VERSION 5.7 ;
BUSBITCHARS "[]" ;
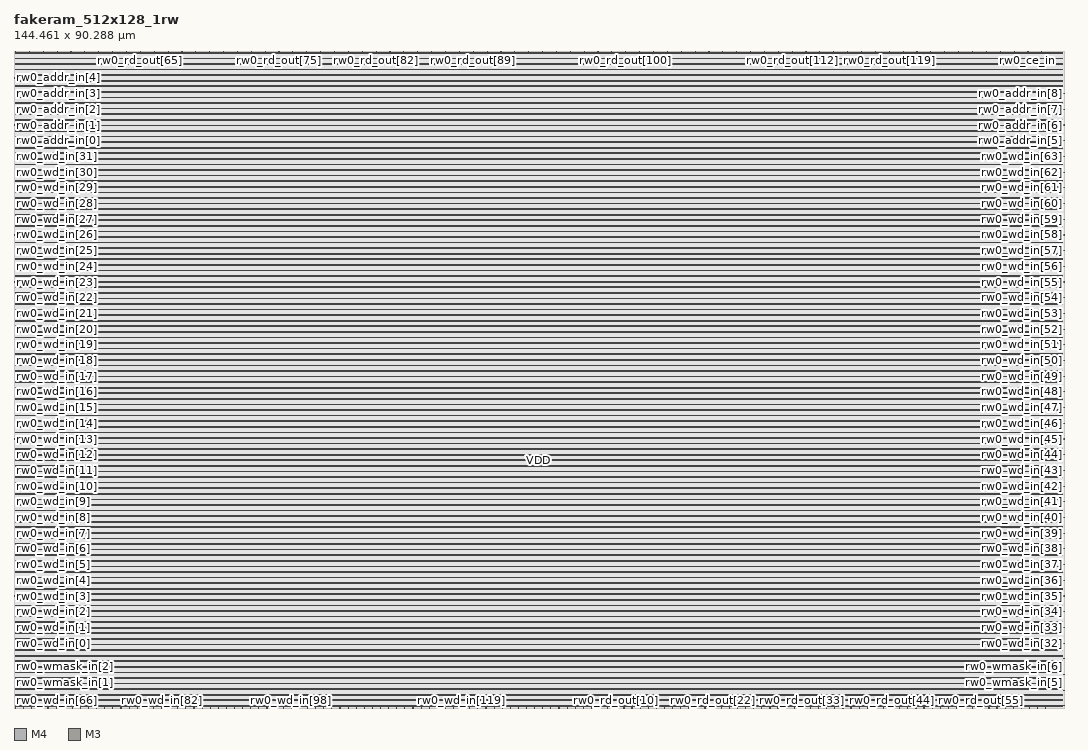
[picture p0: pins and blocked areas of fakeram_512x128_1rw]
MACRO fakeram_512x128_1rw
  FOREIGN fakeram_512x128_1rw 0 0 ;
  SYMMETRY X Y R90 ;
  SIZE 144.461 BY 90.288 ;
  CLASS BLOCK ;
  PIN rw0_wmask_in[0]
    DIRECTION INPUT ;
    USE SIGNAL ;
    SHAPE ABUTMENT ;
    PORT
      LAYER M4 ;
      RECT 0.000 0.276 0.072 0.300 ;
    END
  END rw0_wmask_in[0]
  PIN rw0_wmask_in[1]
    DIRECTION INPUT ;
    USE SIGNAL ;
    SHAPE ABUTMENT ;
    PORT
      LAYER M4 ;
      RECT 0.000 2.436 0.072 2.460 ;
    END
  END rw0_wmask_in[1]
  PIN rw0_wmask_in[2]
    DIRECTION INPUT ;
    USE SIGNAL ;
    SHAPE ABUTMENT ;
    PORT
      LAYER M4 ;
      RECT 0.000 4.596 0.072 4.620 ;
    END
  END rw0_wmask_in[2]
  PIN rw0_wmask_in[3]
    DIRECTION INPUT ;
    USE SIGNAL ;
    SHAPE ABUTMENT ;
    PORT
      LAYER M4 ;
      RECT 0.000 6.756 0.072 6.780 ;
    END
  END rw0_wmask_in[3]
  PIN rw0_wmask_in[4]
    DIRECTION INPUT ;
    USE SIGNAL ;
    SHAPE ABUTMENT ;
    PORT
      LAYER M4 ;
      RECT 144.389 0.276 144.461 0.300 ;
    END
  END rw0_wmask_in[4]
  PIN rw0_wmask_in[5]
    DIRECTION INPUT ;
    USE SIGNAL ;
    SHAPE ABUTMENT ;
    PORT
      LAYER M4 ;
      RECT 144.389 2.436 144.461 2.460 ;
    END
  END rw0_wmask_in[5]
  PIN rw0_wmask_in[6]
    DIRECTION INPUT ;
    USE SIGNAL ;
    SHAPE ABUTMENT ;
    PORT
      LAYER M4 ;
      RECT 144.389 4.596 144.461 4.620 ;
    END
  END rw0_wmask_in[6]
  PIN rw0_wmask_in[7]
    DIRECTION INPUT ;
    USE SIGNAL ;
    SHAPE ABUTMENT ;
    PORT
      LAYER M4 ;
      RECT 144.389 6.756 144.461 6.780 ;
    END
  END rw0_wmask_in[7]
  PIN rw0_wmask_in[8]
    DIRECTION INPUT ;
    USE SIGNAL ;
    SHAPE ABUTMENT ;
    PORT
      LAYER M3 ;
      RECT 0.207 90.234 0.225 90.288 ;
    END
  END rw0_wmask_in[8]
  PIN rw0_wmask_in[9]
    DIRECTION INPUT ;
    USE SIGNAL ;
    SHAPE ABUTMENT ;
    PORT
      LAYER M3 ;
      RECT 2.115 90.234 2.133 90.288 ;
    END
  END rw0_wmask_in[9]
  PIN rw0_wmask_in[10]
    DIRECTION INPUT ;
    USE SIGNAL ;
    SHAPE ABUTMENT ;
    PORT
      LAYER M3 ;
      RECT 4.023 90.234 4.041 90.288 ;
    END
  END rw0_wmask_in[10]
  PIN rw0_wmask_in[11]
    DIRECTION INPUT ;
    USE SIGNAL ;
    SHAPE ABUTMENT ;
    PORT
      LAYER M3 ;
      RECT 5.931 90.234 5.949 90.288 ;
    END
  END rw0_wmask_in[11]
  PIN rw0_wmask_in[12]
    DIRECTION INPUT ;
    USE SIGNAL ;
    SHAPE ABUTMENT ;
    PORT
      LAYER M3 ;
      RECT 7.839 90.234 7.857 90.288 ;
    END
  END rw0_wmask_in[12]
  PIN rw0_wmask_in[13]
    DIRECTION INPUT ;
    USE SIGNAL ;
    SHAPE ABUTMENT ;
    PORT
      LAYER M3 ;
      RECT 9.747 90.234 9.765 90.288 ;
    END
  END rw0_wmask_in[13]
  PIN rw0_wmask_in[14]
    DIRECTION INPUT ;
    USE SIGNAL ;
    SHAPE ABUTMENT ;
    PORT
      LAYER M3 ;
      RECT 11.655 90.234 11.673 90.288 ;
    END
  END rw0_wmask_in[14]
  PIN rw0_wmask_in[15]
    DIRECTION INPUT ;
    USE SIGNAL ;
    SHAPE ABUTMENT ;
    PORT
      LAYER M3 ;
      RECT 13.563 90.234 13.581 90.288 ;
    END
  END rw0_wmask_in[15]
  PIN rw0_wd_in[0]
    DIRECTION INPUT ;
    USE SIGNAL ;
    SHAPE ABUTMENT ;
    PORT
      LAYER M4 ;
      RECT 0.000 8.916 0.072 8.940 ;
    END
  END rw0_wd_in[0]
  PIN rw0_wd_in[1]
    DIRECTION INPUT ;
    USE SIGNAL ;
    SHAPE ABUTMENT ;
    PORT
      LAYER M4 ;
      RECT 0.000 11.076 0.072 11.100 ;
    END
  END rw0_wd_in[1]
  PIN rw0_wd_in[2]
    DIRECTION INPUT ;
    USE SIGNAL ;
    SHAPE ABUTMENT ;
    PORT
      LAYER M4 ;
      RECT 0.000 13.236 0.072 13.260 ;
    END
  END rw0_wd_in[2]
  PIN rw0_wd_in[3]
    DIRECTION INPUT ;
    USE SIGNAL ;
    SHAPE ABUTMENT ;
    PORT
      LAYER M4 ;
      RECT 0.000 15.396 0.072 15.420 ;
    END
  END rw0_wd_in[3]
  PIN rw0_wd_in[4]
    DIRECTION INPUT ;
    USE SIGNAL ;
    SHAPE ABUTMENT ;
    PORT
      LAYER M4 ;
      RECT 0.000 17.556 0.072 17.580 ;
    END
  END rw0_wd_in[4]
  PIN rw0_wd_in[5]
    DIRECTION INPUT ;
    USE SIGNAL ;
    SHAPE ABUTMENT ;
    PORT
      LAYER M4 ;
      RECT 0.000 19.716 0.072 19.740 ;
    END
  END rw0_wd_in[5]
  PIN rw0_wd_in[6]
    DIRECTION INPUT ;
    USE SIGNAL ;
    SHAPE ABUTMENT ;
    PORT
      LAYER M4 ;
      RECT 0.000 21.876 0.072 21.900 ;
    END
  END rw0_wd_in[6]
  PIN rw0_wd_in[7]
    DIRECTION INPUT ;
    USE SIGNAL ;
    SHAPE ABUTMENT ;
    PORT
      LAYER M4 ;
      RECT 0.000 24.036 0.072 24.060 ;
    END
  END rw0_wd_in[7]
  PIN rw0_wd_in[8]
    DIRECTION INPUT ;
    USE SIGNAL ;
    SHAPE ABUTMENT ;
    PORT
      LAYER M4 ;
      RECT 0.000 26.196 0.072 26.220 ;
    END
  END rw0_wd_in[8]
  PIN rw0_wd_in[9]
    DIRECTION INPUT ;
    USE SIGNAL ;
    SHAPE ABUTMENT ;
    PORT
      LAYER M4 ;
      RECT 0.000 28.356 0.072 28.380 ;
    END
  END rw0_wd_in[9]
  PIN rw0_wd_in[10]
    DIRECTION INPUT ;
    USE SIGNAL ;
    SHAPE ABUTMENT ;
    PORT
      LAYER M4 ;
      RECT 0.000 30.516 0.072 30.540 ;
    END
  END rw0_wd_in[10]
  PIN rw0_wd_in[11]
    DIRECTION INPUT ;
    USE SIGNAL ;
    SHAPE ABUTMENT ;
    PORT
      LAYER M4 ;
      RECT 0.000 32.676 0.072 32.700 ;
    END
  END rw0_wd_in[11]
  PIN rw0_wd_in[12]
    DIRECTION INPUT ;
    USE SIGNAL ;
    SHAPE ABUTMENT ;
    PORT
      LAYER M4 ;
      RECT 0.000 34.836 0.072 34.860 ;
    END
  END rw0_wd_in[12]
  PIN rw0_wd_in[13]
    DIRECTION INPUT ;
    USE SIGNAL ;
    SHAPE ABUTMENT ;
    PORT
      LAYER M4 ;
      RECT 0.000 36.996 0.072 37.020 ;
    END
  END rw0_wd_in[13]
  PIN rw0_wd_in[14]
    DIRECTION INPUT ;
    USE SIGNAL ;
    SHAPE ABUTMENT ;
    PORT
      LAYER M4 ;
      RECT 0.000 39.156 0.072 39.180 ;
    END
  END rw0_wd_in[14]
  PIN rw0_wd_in[15]
    DIRECTION INPUT ;
    USE SIGNAL ;
    SHAPE ABUTMENT ;
    PORT
      LAYER M4 ;
      RECT 0.000 41.316 0.072 41.340 ;
    END
  END rw0_wd_in[15]
  PIN rw0_wd_in[16]
    DIRECTION INPUT ;
    USE SIGNAL ;
    SHAPE ABUTMENT ;
    PORT
      LAYER M4 ;
      RECT 0.000 43.476 0.072 43.500 ;
    END
  END rw0_wd_in[16]
  PIN rw0_wd_in[17]
    DIRECTION INPUT ;
    USE SIGNAL ;
    SHAPE ABUTMENT ;
    PORT
      LAYER M4 ;
      RECT 0.000 45.636 0.072 45.660 ;
    END
  END rw0_wd_in[17]
  PIN rw0_wd_in[18]
    DIRECTION INPUT ;
    USE SIGNAL ;
    SHAPE ABUTMENT ;
    PORT
      LAYER M4 ;
      RECT 0.000 47.796 0.072 47.820 ;
    END
  END rw0_wd_in[18]
  PIN rw0_wd_in[19]
    DIRECTION INPUT ;
    USE SIGNAL ;
    SHAPE ABUTMENT ;
    PORT
      LAYER M4 ;
      RECT 0.000 49.956 0.072 49.980 ;
    END
  END rw0_wd_in[19]
  PIN rw0_wd_in[20]
    DIRECTION INPUT ;
    USE SIGNAL ;
    SHAPE ABUTMENT ;
    PORT
      LAYER M4 ;
      RECT 0.000 52.116 0.072 52.140 ;
    END
  END rw0_wd_in[20]
  PIN rw0_wd_in[21]
    DIRECTION INPUT ;
    USE SIGNAL ;
    SHAPE ABUTMENT ;
    PORT
      LAYER M4 ;
      RECT 0.000 54.276 0.072 54.300 ;
    END
  END rw0_wd_in[21]
  PIN rw0_wd_in[22]
    DIRECTION INPUT ;
    USE SIGNAL ;
    SHAPE ABUTMENT ;
    PORT
      LAYER M4 ;
      RECT 0.000 56.436 0.072 56.460 ;
    END
  END rw0_wd_in[22]
  PIN rw0_wd_in[23]
    DIRECTION INPUT ;
    USE SIGNAL ;
    SHAPE ABUTMENT ;
    PORT
      LAYER M4 ;
      RECT 0.000 58.596 0.072 58.620 ;
    END
  END rw0_wd_in[23]
  PIN rw0_wd_in[24]
    DIRECTION INPUT ;
    USE SIGNAL ;
    SHAPE ABUTMENT ;
    PORT
      LAYER M4 ;
      RECT 0.000 60.756 0.072 60.780 ;
    END
  END rw0_wd_in[24]
  PIN rw0_wd_in[25]
    DIRECTION INPUT ;
    USE SIGNAL ;
    SHAPE ABUTMENT ;
    PORT
      LAYER M4 ;
      RECT 0.000 62.916 0.072 62.940 ;
    END
  END rw0_wd_in[25]
  PIN rw0_wd_in[26]
    DIRECTION INPUT ;
    USE SIGNAL ;
    SHAPE ABUTMENT ;
    PORT
      LAYER M4 ;
      RECT 0.000 65.076 0.072 65.100 ;
    END
  END rw0_wd_in[26]
  PIN rw0_wd_in[27]
    DIRECTION INPUT ;
    USE SIGNAL ;
    SHAPE ABUTMENT ;
    PORT
      LAYER M4 ;
      RECT 0.000 67.236 0.072 67.260 ;
    END
  END rw0_wd_in[27]
  PIN rw0_wd_in[28]
    DIRECTION INPUT ;
    USE SIGNAL ;
    SHAPE ABUTMENT ;
    PORT
      LAYER M4 ;
      RECT 0.000 69.396 0.072 69.420 ;
    END
  END rw0_wd_in[28]
  PIN rw0_wd_in[29]
    DIRECTION INPUT ;
    USE SIGNAL ;
    SHAPE ABUTMENT ;
    PORT
      LAYER M4 ;
      RECT 0.000 71.556 0.072 71.580 ;
    END
  END rw0_wd_in[29]
  PIN rw0_wd_in[30]
    DIRECTION INPUT ;
    USE SIGNAL ;
    SHAPE ABUTMENT ;
    PORT
      LAYER M4 ;
      RECT 0.000 73.716 0.072 73.740 ;
    END
  END rw0_wd_in[30]
  PIN rw0_wd_in[31]
    DIRECTION INPUT ;
    USE SIGNAL ;
    SHAPE ABUTMENT ;
    PORT
      LAYER M4 ;
      RECT 0.000 75.876 0.072 75.900 ;
    END
  END rw0_wd_in[31]
  PIN rw0_wd_in[32]
    DIRECTION INPUT ;
    USE SIGNAL ;
    SHAPE ABUTMENT ;
    PORT
      LAYER M4 ;
      RECT 144.389 8.916 144.461 8.940 ;
    END
  END rw0_wd_in[32]
  PIN rw0_wd_in[33]
    DIRECTION INPUT ;
    USE SIGNAL ;
    SHAPE ABUTMENT ;
    PORT
      LAYER M4 ;
      RECT 144.389 11.076 144.461 11.100 ;
    END
  END rw0_wd_in[33]
  PIN rw0_wd_in[34]
    DIRECTION INPUT ;
    USE SIGNAL ;
    SHAPE ABUTMENT ;
    PORT
      LAYER M4 ;
      RECT 144.389 13.236 144.461 13.260 ;
    END
  END rw0_wd_in[34]
  PIN rw0_wd_in[35]
    DIRECTION INPUT ;
    USE SIGNAL ;
    SHAPE ABUTMENT ;
    PORT
      LAYER M4 ;
      RECT 144.389 15.396 144.461 15.420 ;
    END
  END rw0_wd_in[35]
  PIN rw0_wd_in[36]
    DIRECTION INPUT ;
    USE SIGNAL ;
    SHAPE ABUTMENT ;
    PORT
      LAYER M4 ;
      RECT 144.389 17.556 144.461 17.580 ;
    END
  END rw0_wd_in[36]
  PIN rw0_wd_in[37]
    DIRECTION INPUT ;
    USE SIGNAL ;
    SHAPE ABUTMENT ;
    PORT
      LAYER M4 ;
      RECT 144.389 19.716 144.461 19.740 ;
    END
  END rw0_wd_in[37]
  PIN rw0_wd_in[38]
    DIRECTION INPUT ;
    USE SIGNAL ;
    SHAPE ABUTMENT ;
    PORT
      LAYER M4 ;
      RECT 144.389 21.876 144.461 21.900 ;
    END
  END rw0_wd_in[38]
  PIN rw0_wd_in[39]
    DIRECTION INPUT ;
    USE SIGNAL ;
    SHAPE ABUTMENT ;
    PORT
      LAYER M4 ;
      RECT 144.389 24.036 144.461 24.060 ;
    END
  END rw0_wd_in[39]
  PIN rw0_wd_in[40]
    DIRECTION INPUT ;
    USE SIGNAL ;
    SHAPE ABUTMENT ;
    PORT
      LAYER M4 ;
      RECT 144.389 26.196 144.461 26.220 ;
    END
  END rw0_wd_in[40]
  PIN rw0_wd_in[41]
    DIRECTION INPUT ;
    USE SIGNAL ;
    SHAPE ABUTMENT ;
    PORT
      LAYER M4 ;
      RECT 144.389 28.356 144.461 28.380 ;
    END
  END rw0_wd_in[41]
  PIN rw0_wd_in[42]
    DIRECTION INPUT ;
    USE SIGNAL ;
    SHAPE ABUTMENT ;
    PORT
      LAYER M4 ;
      RECT 144.389 30.516 144.461 30.540 ;
    END
  END rw0_wd_in[42]
  PIN rw0_wd_in[43]
    DIRECTION INPUT ;
    USE SIGNAL ;
    SHAPE ABUTMENT ;
    PORT
      LAYER M4 ;
      RECT 144.389 32.676 144.461 32.700 ;
    END
  END rw0_wd_in[43]
  PIN rw0_wd_in[44]
    DIRECTION INPUT ;
    USE SIGNAL ;
    SHAPE ABUTMENT ;
    PORT
      LAYER M4 ;
      RECT 144.389 34.836 144.461 34.860 ;
    END
  END rw0_wd_in[44]
  PIN rw0_wd_in[45]
    DIRECTION INPUT ;
    USE SIGNAL ;
    SHAPE ABUTMENT ;
    PORT
      LAYER M4 ;
      RECT 144.389 36.996 144.461 37.020 ;
    END
  END rw0_wd_in[45]
  PIN rw0_wd_in[46]
    DIRECTION INPUT ;
    USE SIGNAL ;
    SHAPE ABUTMENT ;
    PORT
      LAYER M4 ;
      RECT 144.389 39.156 144.461 39.180 ;
    END
  END rw0_wd_in[46]
  PIN rw0_wd_in[47]
    DIRECTION INPUT ;
    USE SIGNAL ;
    SHAPE ABUTMENT ;
    PORT
      LAYER M4 ;
      RECT 144.389 41.316 144.461 41.340 ;
    END
  END rw0_wd_in[47]
  PIN rw0_wd_in[48]
    DIRECTION INPUT ;
    USE SIGNAL ;
    SHAPE ABUTMENT ;
    PORT
      LAYER M4 ;
      RECT 144.389 43.476 144.461 43.500 ;
    END
  END rw0_wd_in[48]
  PIN rw0_wd_in[49]
    DIRECTION INPUT ;
    USE SIGNAL ;
    SHAPE ABUTMENT ;
    PORT
      LAYER M4 ;
      RECT 144.389 45.636 144.461 45.660 ;
    END
  END rw0_wd_in[49]
  PIN rw0_wd_in[50]
    DIRECTION INPUT ;
    USE SIGNAL ;
    SHAPE ABUTMENT ;
    PORT
      LAYER M4 ;
      RECT 144.389 47.796 144.461 47.820 ;
    END
  END rw0_wd_in[50]
  PIN rw0_wd_in[51]
    DIRECTION INPUT ;
    USE SIGNAL ;
    SHAPE ABUTMENT ;
    PORT
      LAYER M4 ;
      RECT 144.389 49.956 144.461 49.980 ;
    END
  END rw0_wd_in[51]
  PIN rw0_wd_in[52]
    DIRECTION INPUT ;
    USE SIGNAL ;
    SHAPE ABUTMENT ;
    PORT
      LAYER M4 ;
      RECT 144.389 52.116 144.461 52.140 ;
    END
  END rw0_wd_in[52]
  PIN rw0_wd_in[53]
    DIRECTION INPUT ;
    USE SIGNAL ;
    SHAPE ABUTMENT ;
    PORT
      LAYER M4 ;
      RECT 144.389 54.276 144.461 54.300 ;
    END
  END rw0_wd_in[53]
  PIN rw0_wd_in[54]
    DIRECTION INPUT ;
    USE SIGNAL ;
    SHAPE ABUTMENT ;
    PORT
      LAYER M4 ;
      RECT 144.389 56.436 144.461 56.460 ;
    END
  END rw0_wd_in[54]
  PIN rw0_wd_in[55]
    DIRECTION INPUT ;
    USE SIGNAL ;
    SHAPE ABUTMENT ;
    PORT
      LAYER M4 ;
      RECT 144.389 58.596 144.461 58.620 ;
    END
  END rw0_wd_in[55]
  PIN rw0_wd_in[56]
    DIRECTION INPUT ;
    USE SIGNAL ;
    SHAPE ABUTMENT ;
    PORT
      LAYER M4 ;
      RECT 144.389 60.756 144.461 60.780 ;
    END
  END rw0_wd_in[56]
  PIN rw0_wd_in[57]
    DIRECTION INPUT ;
    USE SIGNAL ;
    SHAPE ABUTMENT ;
    PORT
      LAYER M4 ;
      RECT 144.389 62.916 144.461 62.940 ;
    END
  END rw0_wd_in[57]
  PIN rw0_wd_in[58]
    DIRECTION INPUT ;
    USE SIGNAL ;
    SHAPE ABUTMENT ;
    PORT
      LAYER M4 ;
      RECT 144.389 65.076 144.461 65.100 ;
    END
  END rw0_wd_in[58]
  PIN rw0_wd_in[59]
    DIRECTION INPUT ;
    USE SIGNAL ;
    SHAPE ABUTMENT ;
    PORT
      LAYER M4 ;
      RECT 144.389 67.236 144.461 67.260 ;
    END
  END rw0_wd_in[59]
  PIN rw0_wd_in[60]
    DIRECTION INPUT ;
    USE SIGNAL ;
    SHAPE ABUTMENT ;
    PORT
      LAYER M4 ;
      RECT 144.389 69.396 144.461 69.420 ;
    END
  END rw0_wd_in[60]
  PIN rw0_wd_in[61]
    DIRECTION INPUT ;
    USE SIGNAL ;
    SHAPE ABUTMENT ;
    PORT
      LAYER M4 ;
      RECT 144.389 71.556 144.461 71.580 ;
    END
  END rw0_wd_in[61]
  PIN rw0_wd_in[62]
    DIRECTION INPUT ;
    USE SIGNAL ;
    SHAPE ABUTMENT ;
    PORT
      LAYER M4 ;
      RECT 144.389 73.716 144.461 73.740 ;
    END
  END rw0_wd_in[62]
  PIN rw0_wd_in[63]
    DIRECTION INPUT ;
    USE SIGNAL ;
    SHAPE ABUTMENT ;
    PORT
      LAYER M4 ;
      RECT 144.389 75.876 144.461 75.900 ;
    END
  END rw0_wd_in[63]
  PIN rw0_wd_in[64]
    DIRECTION INPUT ;
    USE SIGNAL ;
    SHAPE ABUTMENT ;
    PORT
      LAYER M3 ;
      RECT 0.207 0.000 0.225 0.054 ;
    END
  END rw0_wd_in[64]
  PIN rw0_wd_in[65]
    DIRECTION INPUT ;
    USE SIGNAL ;
    SHAPE ABUTMENT ;
    PORT
      LAYER M3 ;
      RECT 1.323 0.000 1.341 0.054 ;
    END
  END rw0_wd_in[65]
  PIN rw0_wd_in[66]
    DIRECTION INPUT ;
    USE SIGNAL ;
    SHAPE ABUTMENT ;
    PORT
      LAYER M3 ;
      RECT 2.439 0.000 2.457 0.054 ;
    END
  END rw0_wd_in[66]
  PIN rw0_wd_in[67]
    DIRECTION INPUT ;
    USE SIGNAL ;
    SHAPE ABUTMENT ;
    PORT
      LAYER M3 ;
      RECT 3.555 0.000 3.573 0.054 ;
    END
  END rw0_wd_in[67]
  PIN rw0_wd_in[68]
    DIRECTION INPUT ;
    USE SIGNAL ;
    SHAPE ABUTMENT ;
    PORT
      LAYER M3 ;
      RECT 4.671 0.000 4.689 0.054 ;
    END
  END rw0_wd_in[68]
  PIN rw0_wd_in[69]
    DIRECTION INPUT ;
    USE SIGNAL ;
    SHAPE ABUTMENT ;
    PORT
      LAYER M3 ;
      RECT 5.787 0.000 5.805 0.054 ;
    END
  END rw0_wd_in[69]
  PIN rw0_wd_in[70]
    DIRECTION INPUT ;
    USE SIGNAL ;
    SHAPE ABUTMENT ;
    PORT
      LAYER M3 ;
      RECT 6.903 0.000 6.921 0.054 ;
    END
  END rw0_wd_in[70]
  PIN rw0_wd_in[71]
    DIRECTION INPUT ;
    USE SIGNAL ;
    SHAPE ABUTMENT ;
    PORT
      LAYER M3 ;
      RECT 8.019 0.000 8.037 0.054 ;
    END
  END rw0_wd_in[71]
  PIN rw0_wd_in[72]
    DIRECTION INPUT ;
    USE SIGNAL ;
    SHAPE ABUTMENT ;
    PORT
      LAYER M3 ;
      RECT 9.135 0.000 9.153 0.054 ;
    END
  END rw0_wd_in[72]
  PIN rw0_wd_in[73]
    DIRECTION INPUT ;
    USE SIGNAL ;
    SHAPE ABUTMENT ;
    PORT
      LAYER M3 ;
      RECT 10.251 0.000 10.269 0.054 ;
    END
  END rw0_wd_in[73]
  PIN rw0_wd_in[74]
    DIRECTION INPUT ;
    USE SIGNAL ;
    SHAPE ABUTMENT ;
    PORT
      LAYER M3 ;
      RECT 11.367 0.000 11.385 0.054 ;
    END
  END rw0_wd_in[74]
  PIN rw0_wd_in[75]
    DIRECTION INPUT ;
    USE SIGNAL ;
    SHAPE ABUTMENT ;
    PORT
      LAYER M3 ;
      RECT 12.483 0.000 12.501 0.054 ;
    END
  END rw0_wd_in[75]
  PIN rw0_wd_in[76]
    DIRECTION INPUT ;
    USE SIGNAL ;
    SHAPE ABUTMENT ;
    PORT
      LAYER M3 ;
      RECT 13.599 0.000 13.617 0.054 ;
    END
  END rw0_wd_in[76]
  PIN rw0_wd_in[77]
    DIRECTION INPUT ;
    USE SIGNAL ;
    SHAPE ABUTMENT ;
    PORT
      LAYER M3 ;
      RECT 14.715 0.000 14.733 0.054 ;
    END
  END rw0_wd_in[77]
  PIN rw0_wd_in[78]
    DIRECTION INPUT ;
    USE SIGNAL ;
    SHAPE ABUTMENT ;
    PORT
      LAYER M3 ;
      RECT 15.831 0.000 15.849 0.054 ;
    END
  END rw0_wd_in[78]
  PIN rw0_wd_in[79]
    DIRECTION INPUT ;
    USE SIGNAL ;
    SHAPE ABUTMENT ;
    PORT
      LAYER M3 ;
      RECT 16.947 0.000 16.965 0.054 ;
    END
  END rw0_wd_in[79]
  PIN rw0_wd_in[80]
    DIRECTION INPUT ;
    USE SIGNAL ;
    SHAPE ABUTMENT ;
    PORT
      LAYER M3 ;
      RECT 18.063 0.000 18.081 0.054 ;
    END
  END rw0_wd_in[80]
  PIN rw0_wd_in[81]
    DIRECTION INPUT ;
    USE SIGNAL ;
    SHAPE ABUTMENT ;
    PORT
      LAYER M3 ;
      RECT 19.179 0.000 19.197 0.054 ;
    END
  END rw0_wd_in[81]
  PIN rw0_wd_in[82]
    DIRECTION INPUT ;
    USE SIGNAL ;
    SHAPE ABUTMENT ;
    PORT
      LAYER M3 ;
      RECT 20.295 0.000 20.313 0.054 ;
    END
  END rw0_wd_in[82]
  PIN rw0_wd_in[83]
    DIRECTION INPUT ;
    USE SIGNAL ;
    SHAPE ABUTMENT ;
    PORT
      LAYER M3 ;
      RECT 21.411 0.000 21.429 0.054 ;
    END
  END rw0_wd_in[83]
  PIN rw0_wd_in[84]
    DIRECTION INPUT ;
    USE SIGNAL ;
    SHAPE ABUTMENT ;
    PORT
      LAYER M3 ;
      RECT 22.527 0.000 22.545 0.054 ;
    END
  END rw0_wd_in[84]
  PIN rw0_wd_in[85]
    DIRECTION INPUT ;
    USE SIGNAL ;
    SHAPE ABUTMENT ;
    PORT
      LAYER M3 ;
      RECT 23.643 0.000 23.661 0.054 ;
    END
  END rw0_wd_in[85]
  PIN rw0_wd_in[86]
    DIRECTION INPUT ;
    USE SIGNAL ;
    SHAPE ABUTMENT ;
    PORT
      LAYER M3 ;
      RECT 24.759 0.000 24.777 0.054 ;
    END
  END rw0_wd_in[86]
  PIN rw0_wd_in[87]
    DIRECTION INPUT ;
    USE SIGNAL ;
    SHAPE ABUTMENT ;
    PORT
      LAYER M3 ;
      RECT 25.875 0.000 25.893 0.054 ;
    END
  END rw0_wd_in[87]
  PIN rw0_wd_in[88]
    DIRECTION INPUT ;
    USE SIGNAL ;
    SHAPE ABUTMENT ;
    PORT
      LAYER M3 ;
      RECT 26.991 0.000 27.009 0.054 ;
    END
  END rw0_wd_in[88]
  PIN rw0_wd_in[89]
    DIRECTION INPUT ;
    USE SIGNAL ;
    SHAPE ABUTMENT ;
    PORT
      LAYER M3 ;
      RECT 28.107 0.000 28.125 0.054 ;
    END
  END rw0_wd_in[89]
  PIN rw0_wd_in[90]
    DIRECTION INPUT ;
    USE SIGNAL ;
    SHAPE ABUTMENT ;
    PORT
      LAYER M3 ;
      RECT 29.223 0.000 29.241 0.054 ;
    END
  END rw0_wd_in[90]
  PIN rw0_wd_in[91]
    DIRECTION INPUT ;
    USE SIGNAL ;
    SHAPE ABUTMENT ;
    PORT
      LAYER M3 ;
      RECT 30.339 0.000 30.357 0.054 ;
    END
  END rw0_wd_in[91]
  PIN rw0_wd_in[92]
    DIRECTION INPUT ;
    USE SIGNAL ;
    SHAPE ABUTMENT ;
    PORT
      LAYER M3 ;
      RECT 31.455 0.000 31.473 0.054 ;
    END
  END rw0_wd_in[92]
  PIN rw0_wd_in[93]
    DIRECTION INPUT ;
    USE SIGNAL ;
    SHAPE ABUTMENT ;
    PORT
      LAYER M3 ;
      RECT 32.571 0.000 32.589 0.054 ;
    END
  END rw0_wd_in[93]
  PIN rw0_wd_in[94]
    DIRECTION INPUT ;
    USE SIGNAL ;
    SHAPE ABUTMENT ;
    PORT
      LAYER M3 ;
      RECT 33.687 0.000 33.705 0.054 ;
    END
  END rw0_wd_in[94]
  PIN rw0_wd_in[95]
    DIRECTION INPUT ;
    USE SIGNAL ;
    SHAPE ABUTMENT ;
    PORT
      LAYER M3 ;
      RECT 34.803 0.000 34.821 0.054 ;
    END
  END rw0_wd_in[95]
  PIN rw0_wd_in[96]
    DIRECTION INPUT ;
    USE SIGNAL ;
    SHAPE ABUTMENT ;
    PORT
      LAYER M3 ;
      RECT 35.919 0.000 35.937 0.054 ;
    END
  END rw0_wd_in[96]
  PIN rw0_wd_in[97]
    DIRECTION INPUT ;
    USE SIGNAL ;
    SHAPE ABUTMENT ;
    PORT
      LAYER M3 ;
      RECT 37.035 0.000 37.053 0.054 ;
    END
  END rw0_wd_in[97]
  PIN rw0_wd_in[98]
    DIRECTION INPUT ;
    USE SIGNAL ;
    SHAPE ABUTMENT ;
    PORT
      LAYER M3 ;
      RECT 38.151 0.000 38.169 0.054 ;
    END
  END rw0_wd_in[98]
  PIN rw0_wd_in[99]
    DIRECTION INPUT ;
    USE SIGNAL ;
    SHAPE ABUTMENT ;
    PORT
      LAYER M3 ;
      RECT 39.267 0.000 39.285 0.054 ;
    END
  END rw0_wd_in[99]
  PIN rw0_wd_in[100]
    DIRECTION INPUT ;
    USE SIGNAL ;
    SHAPE ABUTMENT ;
    PORT
      LAYER M3 ;
      RECT 40.383 0.000 40.401 0.054 ;
    END
  END rw0_wd_in[100]
  PIN rw0_wd_in[101]
    DIRECTION INPUT ;
    USE SIGNAL ;
    SHAPE ABUTMENT ;
    PORT
      LAYER M3 ;
      RECT 41.499 0.000 41.517 0.054 ;
    END
  END rw0_wd_in[101]
  PIN rw0_wd_in[102]
    DIRECTION INPUT ;
    USE SIGNAL ;
    SHAPE ABUTMENT ;
    PORT
      LAYER M3 ;
      RECT 42.615 0.000 42.633 0.054 ;
    END
  END rw0_wd_in[102]
  PIN rw0_wd_in[103]
    DIRECTION INPUT ;
    USE SIGNAL ;
    SHAPE ABUTMENT ;
    PORT
      LAYER M3 ;
      RECT 43.731 0.000 43.749 0.054 ;
    END
  END rw0_wd_in[103]
  PIN rw0_wd_in[104]
    DIRECTION INPUT ;
    USE SIGNAL ;
    SHAPE ABUTMENT ;
    PORT
      LAYER M3 ;
      RECT 44.847 0.000 44.865 0.054 ;
    END
  END rw0_wd_in[104]
  PIN rw0_wd_in[105]
    DIRECTION INPUT ;
    USE SIGNAL ;
    SHAPE ABUTMENT ;
    PORT
      LAYER M3 ;
      RECT 45.963 0.000 45.981 0.054 ;
    END
  END rw0_wd_in[105]
  PIN rw0_wd_in[106]
    DIRECTION INPUT ;
    USE SIGNAL ;
    SHAPE ABUTMENT ;
    PORT
      LAYER M3 ;
      RECT 47.079 0.000 47.097 0.054 ;
    END
  END rw0_wd_in[106]
  PIN rw0_wd_in[107]
    DIRECTION INPUT ;
    USE SIGNAL ;
    SHAPE ABUTMENT ;
    PORT
      LAYER M3 ;
      RECT 48.195 0.000 48.213 0.054 ;
    END
  END rw0_wd_in[107]
  PIN rw0_wd_in[108]
    DIRECTION INPUT ;
    USE SIGNAL ;
    SHAPE ABUTMENT ;
    PORT
      LAYER M3 ;
      RECT 49.311 0.000 49.329 0.054 ;
    END
  END rw0_wd_in[108]
  PIN rw0_wd_in[109]
    DIRECTION INPUT ;
    USE SIGNAL ;
    SHAPE ABUTMENT ;
    PORT
      LAYER M3 ;
      RECT 50.427 0.000 50.445 0.054 ;
    END
  END rw0_wd_in[109]
  PIN rw0_wd_in[110]
    DIRECTION INPUT ;
    USE SIGNAL ;
    SHAPE ABUTMENT ;
    PORT
      LAYER M3 ;
      RECT 51.543 0.000 51.561 0.054 ;
    END
  END rw0_wd_in[110]
  PIN rw0_wd_in[111]
    DIRECTION INPUT ;
    USE SIGNAL ;
    SHAPE ABUTMENT ;
    PORT
      LAYER M3 ;
      RECT 52.659 0.000 52.677 0.054 ;
    END
  END rw0_wd_in[111]
  PIN rw0_wd_in[112]
    DIRECTION INPUT ;
    USE SIGNAL ;
    SHAPE ABUTMENT ;
    PORT
      LAYER M3 ;
      RECT 53.775 0.000 53.793 0.054 ;
    END
  END rw0_wd_in[112]
  PIN rw0_wd_in[113]
    DIRECTION INPUT ;
    USE SIGNAL ;
    SHAPE ABUTMENT ;
    PORT
      LAYER M3 ;
      RECT 54.891 0.000 54.909 0.054 ;
    END
  END rw0_wd_in[113]
  PIN rw0_wd_in[114]
    DIRECTION INPUT ;
    USE SIGNAL ;
    SHAPE ABUTMENT ;
    PORT
      LAYER M3 ;
      RECT 56.007 0.000 56.025 0.054 ;
    END
  END rw0_wd_in[114]
  PIN rw0_wd_in[115]
    DIRECTION INPUT ;
    USE SIGNAL ;
    SHAPE ABUTMENT ;
    PORT
      LAYER M3 ;
      RECT 57.123 0.000 57.141 0.054 ;
    END
  END rw0_wd_in[115]
  PIN rw0_wd_in[116]
    DIRECTION INPUT ;
    USE SIGNAL ;
    SHAPE ABUTMENT ;
    PORT
      LAYER M3 ;
      RECT 58.239 0.000 58.257 0.054 ;
    END
  END rw0_wd_in[116]
  PIN rw0_wd_in[117]
    DIRECTION INPUT ;
    USE SIGNAL ;
    SHAPE ABUTMENT ;
    PORT
      LAYER M3 ;
      RECT 59.355 0.000 59.373 0.054 ;
    END
  END rw0_wd_in[117]
  PIN rw0_wd_in[118]
    DIRECTION INPUT ;
    USE SIGNAL ;
    SHAPE ABUTMENT ;
    PORT
      LAYER M3 ;
      RECT 60.471 0.000 60.489 0.054 ;
    END
  END rw0_wd_in[118]
  PIN rw0_wd_in[119]
    DIRECTION INPUT ;
    USE SIGNAL ;
    SHAPE ABUTMENT ;
    PORT
      LAYER M3 ;
      RECT 61.587 0.000 61.605 0.054 ;
    END
  END rw0_wd_in[119]
  PIN rw0_wd_in[120]
    DIRECTION INPUT ;
    USE SIGNAL ;
    SHAPE ABUTMENT ;
    PORT
      LAYER M3 ;
      RECT 62.703 0.000 62.721 0.054 ;
    END
  END rw0_wd_in[120]
  PIN rw0_wd_in[121]
    DIRECTION INPUT ;
    USE SIGNAL ;
    SHAPE ABUTMENT ;
    PORT
      LAYER M3 ;
      RECT 63.819 0.000 63.837 0.054 ;
    END
  END rw0_wd_in[121]
  PIN rw0_wd_in[122]
    DIRECTION INPUT ;
    USE SIGNAL ;
    SHAPE ABUTMENT ;
    PORT
      LAYER M3 ;
      RECT 64.935 0.000 64.953 0.054 ;
    END
  END rw0_wd_in[122]
  PIN rw0_wd_in[123]
    DIRECTION INPUT ;
    USE SIGNAL ;
    SHAPE ABUTMENT ;
    PORT
      LAYER M3 ;
      RECT 66.051 0.000 66.069 0.054 ;
    END
  END rw0_wd_in[123]
  PIN rw0_wd_in[124]
    DIRECTION INPUT ;
    USE SIGNAL ;
    SHAPE ABUTMENT ;
    PORT
      LAYER M3 ;
      RECT 67.167 0.000 67.185 0.054 ;
    END
  END rw0_wd_in[124]
  PIN rw0_wd_in[125]
    DIRECTION INPUT ;
    USE SIGNAL ;
    SHAPE ABUTMENT ;
    PORT
      LAYER M3 ;
      RECT 68.283 0.000 68.301 0.054 ;
    END
  END rw0_wd_in[125]
  PIN rw0_wd_in[126]
    DIRECTION INPUT ;
    USE SIGNAL ;
    SHAPE ABUTMENT ;
    PORT
      LAYER M3 ;
      RECT 69.399 0.000 69.417 0.054 ;
    END
  END rw0_wd_in[126]
  PIN rw0_wd_in[127]
    DIRECTION INPUT ;
    USE SIGNAL ;
    SHAPE ABUTMENT ;
    PORT
      LAYER M3 ;
      RECT 70.515 0.000 70.533 0.054 ;
    END
  END rw0_wd_in[127]
  PIN rw0_rd_out[0]
    DIRECTION OUTPUT ;
    USE SIGNAL ;
    SHAPE ABUTMENT ;
    PORT
      LAYER M3 ;
      RECT 71.631 0.000 71.649 0.054 ;
    END
  END rw0_rd_out[0]
  PIN rw0_rd_out[1]
    DIRECTION OUTPUT ;
    USE SIGNAL ;
    SHAPE ABUTMENT ;
    PORT
      LAYER M3 ;
      RECT 72.747 0.000 72.765 0.054 ;
    END
  END rw0_rd_out[1]
  PIN rw0_rd_out[2]
    DIRECTION OUTPUT ;
    USE SIGNAL ;
    SHAPE ABUTMENT ;
    PORT
      LAYER M3 ;
      RECT 73.863 0.000 73.881 0.054 ;
    END
  END rw0_rd_out[2]
  PIN rw0_rd_out[3]
    DIRECTION OUTPUT ;
    USE SIGNAL ;
    SHAPE ABUTMENT ;
    PORT
      LAYER M3 ;
      RECT 74.979 0.000 74.997 0.054 ;
    END
  END rw0_rd_out[3]
  PIN rw0_rd_out[4]
    DIRECTION OUTPUT ;
    USE SIGNAL ;
    SHAPE ABUTMENT ;
    PORT
      LAYER M3 ;
      RECT 76.095 0.000 76.113 0.054 ;
    END
  END rw0_rd_out[4]
  PIN rw0_rd_out[5]
    DIRECTION OUTPUT ;
    USE SIGNAL ;
    SHAPE ABUTMENT ;
    PORT
      LAYER M3 ;
      RECT 77.211 0.000 77.229 0.054 ;
    END
  END rw0_rd_out[5]
  PIN rw0_rd_out[6]
    DIRECTION OUTPUT ;
    USE SIGNAL ;
    SHAPE ABUTMENT ;
    PORT
      LAYER M3 ;
      RECT 78.327 0.000 78.345 0.054 ;
    END
  END rw0_rd_out[6]
  PIN rw0_rd_out[7]
    DIRECTION OUTPUT ;
    USE SIGNAL ;
    SHAPE ABUTMENT ;
    PORT
      LAYER M3 ;
      RECT 79.443 0.000 79.461 0.054 ;
    END
  END rw0_rd_out[7]
  PIN rw0_rd_out[8]
    DIRECTION OUTPUT ;
    USE SIGNAL ;
    SHAPE ABUTMENT ;
    PORT
      LAYER M3 ;
      RECT 80.559 0.000 80.577 0.054 ;
    END
  END rw0_rd_out[8]
  PIN rw0_rd_out[9]
    DIRECTION OUTPUT ;
    USE SIGNAL ;
    SHAPE ABUTMENT ;
    PORT
      LAYER M3 ;
      RECT 81.675 0.000 81.693 0.054 ;
    END
  END rw0_rd_out[9]
  PIN rw0_rd_out[10]
    DIRECTION OUTPUT ;
    USE SIGNAL ;
    SHAPE ABUTMENT ;
    PORT
      LAYER M3 ;
      RECT 82.791 0.000 82.809 0.054 ;
    END
  END rw0_rd_out[10]
  PIN rw0_rd_out[11]
    DIRECTION OUTPUT ;
    USE SIGNAL ;
    SHAPE ABUTMENT ;
    PORT
      LAYER M3 ;
      RECT 83.907 0.000 83.925 0.054 ;
    END
  END rw0_rd_out[11]
  PIN rw0_rd_out[12]
    DIRECTION OUTPUT ;
    USE SIGNAL ;
    SHAPE ABUTMENT ;
    PORT
      LAYER M3 ;
      RECT 85.023 0.000 85.041 0.054 ;
    END
  END rw0_rd_out[12]
  PIN rw0_rd_out[13]
    DIRECTION OUTPUT ;
    USE SIGNAL ;
    SHAPE ABUTMENT ;
    PORT
      LAYER M3 ;
      RECT 86.139 0.000 86.157 0.054 ;
    END
  END rw0_rd_out[13]
  PIN rw0_rd_out[14]
    DIRECTION OUTPUT ;
    USE SIGNAL ;
    SHAPE ABUTMENT ;
    PORT
      LAYER M3 ;
      RECT 87.255 0.000 87.273 0.054 ;
    END
  END rw0_rd_out[14]
  PIN rw0_rd_out[15]
    DIRECTION OUTPUT ;
    USE SIGNAL ;
    SHAPE ABUTMENT ;
    PORT
      LAYER M3 ;
      RECT 88.371 0.000 88.389 0.054 ;
    END
  END rw0_rd_out[15]
  PIN rw0_rd_out[16]
    DIRECTION OUTPUT ;
    USE SIGNAL ;
    SHAPE ABUTMENT ;
    PORT
      LAYER M3 ;
      RECT 89.487 0.000 89.505 0.054 ;
    END
  END rw0_rd_out[16]
  PIN rw0_rd_out[17]
    DIRECTION OUTPUT ;
    USE SIGNAL ;
    SHAPE ABUTMENT ;
    PORT
      LAYER M3 ;
      RECT 90.603 0.000 90.621 0.054 ;
    END
  END rw0_rd_out[17]
  PIN rw0_rd_out[18]
    DIRECTION OUTPUT ;
    USE SIGNAL ;
    SHAPE ABUTMENT ;
    PORT
      LAYER M3 ;
      RECT 91.719 0.000 91.737 0.054 ;
    END
  END rw0_rd_out[18]
  PIN rw0_rd_out[19]
    DIRECTION OUTPUT ;
    USE SIGNAL ;
    SHAPE ABUTMENT ;
    PORT
      LAYER M3 ;
      RECT 92.835 0.000 92.853 0.054 ;
    END
  END rw0_rd_out[19]
  PIN rw0_rd_out[20]
    DIRECTION OUTPUT ;
    USE SIGNAL ;
    SHAPE ABUTMENT ;
    PORT
      LAYER M3 ;
      RECT 93.951 0.000 93.969 0.054 ;
    END
  END rw0_rd_out[20]
  PIN rw0_rd_out[21]
    DIRECTION OUTPUT ;
    USE SIGNAL ;
    SHAPE ABUTMENT ;
    PORT
      LAYER M3 ;
      RECT 95.067 0.000 95.085 0.054 ;
    END
  END rw0_rd_out[21]
  PIN rw0_rd_out[22]
    DIRECTION OUTPUT ;
    USE SIGNAL ;
    SHAPE ABUTMENT ;
    PORT
      LAYER M3 ;
      RECT 96.183 0.000 96.201 0.054 ;
    END
  END rw0_rd_out[22]
  PIN rw0_rd_out[23]
    DIRECTION OUTPUT ;
    USE SIGNAL ;
    SHAPE ABUTMENT ;
    PORT
      LAYER M3 ;
      RECT 97.299 0.000 97.317 0.054 ;
    END
  END rw0_rd_out[23]
  PIN rw0_rd_out[24]
    DIRECTION OUTPUT ;
    USE SIGNAL ;
    SHAPE ABUTMENT ;
    PORT
      LAYER M3 ;
      RECT 98.415 0.000 98.433 0.054 ;
    END
  END rw0_rd_out[24]
  PIN rw0_rd_out[25]
    DIRECTION OUTPUT ;
    USE SIGNAL ;
    SHAPE ABUTMENT ;
    PORT
      LAYER M3 ;
      RECT 99.531 0.000 99.549 0.054 ;
    END
  END rw0_rd_out[25]
  PIN rw0_rd_out[26]
    DIRECTION OUTPUT ;
    USE SIGNAL ;
    SHAPE ABUTMENT ;
    PORT
      LAYER M3 ;
      RECT 100.647 0.000 100.665 0.054 ;
    END
  END rw0_rd_out[26]
  PIN rw0_rd_out[27]
    DIRECTION OUTPUT ;
    USE SIGNAL ;
    SHAPE ABUTMENT ;
    PORT
      LAYER M3 ;
      RECT 101.763 0.000 101.781 0.054 ;
    END
  END rw0_rd_out[27]
  PIN rw0_rd_out[28]
    DIRECTION OUTPUT ;
    USE SIGNAL ;
    SHAPE ABUTMENT ;
    PORT
      LAYER M3 ;
      RECT 102.879 0.000 102.897 0.054 ;
    END
  END rw0_rd_out[28]
  PIN rw0_rd_out[29]
    DIRECTION OUTPUT ;
    USE SIGNAL ;
    SHAPE ABUTMENT ;
    PORT
      LAYER M3 ;
      RECT 103.995 0.000 104.013 0.054 ;
    END
  END rw0_rd_out[29]
  PIN rw0_rd_out[30]
    DIRECTION OUTPUT ;
    USE SIGNAL ;
    SHAPE ABUTMENT ;
    PORT
      LAYER M3 ;
      RECT 105.111 0.000 105.129 0.054 ;
    END
  END rw0_rd_out[30]
  PIN rw0_rd_out[31]
    DIRECTION OUTPUT ;
    USE SIGNAL ;
    SHAPE ABUTMENT ;
    PORT
      LAYER M3 ;
      RECT 106.227 0.000 106.245 0.054 ;
    END
  END rw0_rd_out[31]
  PIN rw0_rd_out[32]
    DIRECTION OUTPUT ;
    USE SIGNAL ;
    SHAPE ABUTMENT ;
    PORT
      LAYER M3 ;
      RECT 107.343 0.000 107.361 0.054 ;
    END
  END rw0_rd_out[32]
  PIN rw0_rd_out[33]
    DIRECTION OUTPUT ;
    USE SIGNAL ;
    SHAPE ABUTMENT ;
    PORT
      LAYER M3 ;
      RECT 108.459 0.000 108.477 0.054 ;
    END
  END rw0_rd_out[33]
  PIN rw0_rd_out[34]
    DIRECTION OUTPUT ;
    USE SIGNAL ;
    SHAPE ABUTMENT ;
    PORT
      LAYER M3 ;
      RECT 109.575 0.000 109.593 0.054 ;
    END
  END rw0_rd_out[34]
  PIN rw0_rd_out[35]
    DIRECTION OUTPUT ;
    USE SIGNAL ;
    SHAPE ABUTMENT ;
    PORT
      LAYER M3 ;
      RECT 110.691 0.000 110.709 0.054 ;
    END
  END rw0_rd_out[35]
  PIN rw0_rd_out[36]
    DIRECTION OUTPUT ;
    USE SIGNAL ;
    SHAPE ABUTMENT ;
    PORT
      LAYER M3 ;
      RECT 111.807 0.000 111.825 0.054 ;
    END
  END rw0_rd_out[36]
  PIN rw0_rd_out[37]
    DIRECTION OUTPUT ;
    USE SIGNAL ;
    SHAPE ABUTMENT ;
    PORT
      LAYER M3 ;
      RECT 112.923 0.000 112.941 0.054 ;
    END
  END rw0_rd_out[37]
  PIN rw0_rd_out[38]
    DIRECTION OUTPUT ;
    USE SIGNAL ;
    SHAPE ABUTMENT ;
    PORT
      LAYER M3 ;
      RECT 114.039 0.000 114.057 0.054 ;
    END
  END rw0_rd_out[38]
  PIN rw0_rd_out[39]
    DIRECTION OUTPUT ;
    USE SIGNAL ;
    SHAPE ABUTMENT ;
    PORT
      LAYER M3 ;
      RECT 115.155 0.000 115.173 0.054 ;
    END
  END rw0_rd_out[39]
  PIN rw0_rd_out[40]
    DIRECTION OUTPUT ;
    USE SIGNAL ;
    SHAPE ABUTMENT ;
    PORT
      LAYER M3 ;
      RECT 116.271 0.000 116.289 0.054 ;
    END
  END rw0_rd_out[40]
  PIN rw0_rd_out[41]
    DIRECTION OUTPUT ;
    USE SIGNAL ;
    SHAPE ABUTMENT ;
    PORT
      LAYER M3 ;
      RECT 117.387 0.000 117.405 0.054 ;
    END
  END rw0_rd_out[41]
  PIN rw0_rd_out[42]
    DIRECTION OUTPUT ;
    USE SIGNAL ;
    SHAPE ABUTMENT ;
    PORT
      LAYER M3 ;
      RECT 118.503 0.000 118.521 0.054 ;
    END
  END rw0_rd_out[42]
  PIN rw0_rd_out[43]
    DIRECTION OUTPUT ;
    USE SIGNAL ;
    SHAPE ABUTMENT ;
    PORT
      LAYER M3 ;
      RECT 119.619 0.000 119.637 0.054 ;
    END
  END rw0_rd_out[43]
  PIN rw0_rd_out[44]
    DIRECTION OUTPUT ;
    USE SIGNAL ;
    SHAPE ABUTMENT ;
    PORT
      LAYER M3 ;
      RECT 120.735 0.000 120.753 0.054 ;
    END
  END rw0_rd_out[44]
  PIN rw0_rd_out[45]
    DIRECTION OUTPUT ;
    USE SIGNAL ;
    SHAPE ABUTMENT ;
    PORT
      LAYER M3 ;
      RECT 121.851 0.000 121.869 0.054 ;
    END
  END rw0_rd_out[45]
  PIN rw0_rd_out[46]
    DIRECTION OUTPUT ;
    USE SIGNAL ;
    SHAPE ABUTMENT ;
    PORT
      LAYER M3 ;
      RECT 122.967 0.000 122.985 0.054 ;
    END
  END rw0_rd_out[46]
  PIN rw0_rd_out[47]
    DIRECTION OUTPUT ;
    USE SIGNAL ;
    SHAPE ABUTMENT ;
    PORT
      LAYER M3 ;
      RECT 124.083 0.000 124.101 0.054 ;
    END
  END rw0_rd_out[47]
  PIN rw0_rd_out[48]
    DIRECTION OUTPUT ;
    USE SIGNAL ;
    SHAPE ABUTMENT ;
    PORT
      LAYER M3 ;
      RECT 125.199 0.000 125.217 0.054 ;
    END
  END rw0_rd_out[48]
  PIN rw0_rd_out[49]
    DIRECTION OUTPUT ;
    USE SIGNAL ;
    SHAPE ABUTMENT ;
    PORT
      LAYER M3 ;
      RECT 126.315 0.000 126.333 0.054 ;
    END
  END rw0_rd_out[49]
  PIN rw0_rd_out[50]
    DIRECTION OUTPUT ;
    USE SIGNAL ;
    SHAPE ABUTMENT ;
    PORT
      LAYER M3 ;
      RECT 127.431 0.000 127.449 0.054 ;
    END
  END rw0_rd_out[50]
  PIN rw0_rd_out[51]
    DIRECTION OUTPUT ;
    USE SIGNAL ;
    SHAPE ABUTMENT ;
    PORT
      LAYER M3 ;
      RECT 128.547 0.000 128.565 0.054 ;
    END
  END rw0_rd_out[51]
  PIN rw0_rd_out[52]
    DIRECTION OUTPUT ;
    USE SIGNAL ;
    SHAPE ABUTMENT ;
    PORT
      LAYER M3 ;
      RECT 129.663 0.000 129.681 0.054 ;
    END
  END rw0_rd_out[52]
  PIN rw0_rd_out[53]
    DIRECTION OUTPUT ;
    USE SIGNAL ;
    SHAPE ABUTMENT ;
    PORT
      LAYER M3 ;
      RECT 130.779 0.000 130.797 0.054 ;
    END
  END rw0_rd_out[53]
  PIN rw0_rd_out[54]
    DIRECTION OUTPUT ;
    USE SIGNAL ;
    SHAPE ABUTMENT ;
    PORT
      LAYER M3 ;
      RECT 131.895 0.000 131.913 0.054 ;
    END
  END rw0_rd_out[54]
  PIN rw0_rd_out[55]
    DIRECTION OUTPUT ;
    USE SIGNAL ;
    SHAPE ABUTMENT ;
    PORT
      LAYER M3 ;
      RECT 133.011 0.000 133.029 0.054 ;
    END
  END rw0_rd_out[55]
  PIN rw0_rd_out[56]
    DIRECTION OUTPUT ;
    USE SIGNAL ;
    SHAPE ABUTMENT ;
    PORT
      LAYER M3 ;
      RECT 134.127 0.000 134.145 0.054 ;
    END
  END rw0_rd_out[56]
  PIN rw0_rd_out[57]
    DIRECTION OUTPUT ;
    USE SIGNAL ;
    SHAPE ABUTMENT ;
    PORT
      LAYER M3 ;
      RECT 135.243 0.000 135.261 0.054 ;
    END
  END rw0_rd_out[57]
  PIN rw0_rd_out[58]
    DIRECTION OUTPUT ;
    USE SIGNAL ;
    SHAPE ABUTMENT ;
    PORT
      LAYER M3 ;
      RECT 136.359 0.000 136.377 0.054 ;
    END
  END rw0_rd_out[58]
  PIN rw0_rd_out[59]
    DIRECTION OUTPUT ;
    USE SIGNAL ;
    SHAPE ABUTMENT ;
    PORT
      LAYER M3 ;
      RECT 137.475 0.000 137.493 0.054 ;
    END
  END rw0_rd_out[59]
  PIN rw0_rd_out[60]
    DIRECTION OUTPUT ;
    USE SIGNAL ;
    SHAPE ABUTMENT ;
    PORT
      LAYER M3 ;
      RECT 138.591 0.000 138.609 0.054 ;
    END
  END rw0_rd_out[60]
  PIN rw0_rd_out[61]
    DIRECTION OUTPUT ;
    USE SIGNAL ;
    SHAPE ABUTMENT ;
    PORT
      LAYER M3 ;
      RECT 139.707 0.000 139.725 0.054 ;
    END
  END rw0_rd_out[61]
  PIN rw0_rd_out[62]
    DIRECTION OUTPUT ;
    USE SIGNAL ;
    SHAPE ABUTMENT ;
    PORT
      LAYER M3 ;
      RECT 140.823 0.000 140.841 0.054 ;
    END
  END rw0_rd_out[62]
  PIN rw0_rd_out[63]
    DIRECTION OUTPUT ;
    USE SIGNAL ;
    SHAPE ABUTMENT ;
    PORT
      LAYER M3 ;
      RECT 141.939 0.000 141.957 0.054 ;
    END
  END rw0_rd_out[63]
  PIN rw0_rd_out[64]
    DIRECTION OUTPUT ;
    USE SIGNAL ;
    SHAPE ABUTMENT ;
    PORT
      LAYER M3 ;
      RECT 15.471 90.234 15.489 90.288 ;
    END
  END rw0_rd_out[64]
  PIN rw0_rd_out[65]
    DIRECTION OUTPUT ;
    USE SIGNAL ;
    SHAPE ABUTMENT ;
    PORT
      LAYER M3 ;
      RECT 17.379 90.234 17.397 90.288 ;
    END
  END rw0_rd_out[65]
  PIN rw0_rd_out[66]
    DIRECTION OUTPUT ;
    USE SIGNAL ;
    SHAPE ABUTMENT ;
    PORT
      LAYER M3 ;
      RECT 19.287 90.234 19.305 90.288 ;
    END
  END rw0_rd_out[66]
  PIN rw0_rd_out[67]
    DIRECTION OUTPUT ;
    USE SIGNAL ;
    SHAPE ABUTMENT ;
    PORT
      LAYER M3 ;
      RECT 21.195 90.234 21.213 90.288 ;
    END
  END rw0_rd_out[67]
  PIN rw0_rd_out[68]
    DIRECTION OUTPUT ;
    USE SIGNAL ;
    SHAPE ABUTMENT ;
    PORT
      LAYER M3 ;
      RECT 23.103 90.234 23.121 90.288 ;
    END
  END rw0_rd_out[68]
  PIN rw0_rd_out[69]
    DIRECTION OUTPUT ;
    USE SIGNAL ;
    SHAPE ABUTMENT ;
    PORT
      LAYER M3 ;
      RECT 25.011 90.234 25.029 90.288 ;
    END
  END rw0_rd_out[69]
  PIN rw0_rd_out[70]
    DIRECTION OUTPUT ;
    USE SIGNAL ;
    SHAPE ABUTMENT ;
    PORT
      LAYER M3 ;
      RECT 26.919 90.234 26.937 90.288 ;
    END
  END rw0_rd_out[70]
  PIN rw0_rd_out[71]
    DIRECTION OUTPUT ;
    USE SIGNAL ;
    SHAPE ABUTMENT ;
    PORT
      LAYER M3 ;
      RECT 28.827 90.234 28.845 90.288 ;
    END
  END rw0_rd_out[71]
  PIN rw0_rd_out[72]
    DIRECTION OUTPUT ;
    USE SIGNAL ;
    SHAPE ABUTMENT ;
    PORT
      LAYER M3 ;
      RECT 30.735 90.234 30.753 90.288 ;
    END
  END rw0_rd_out[72]
  PIN rw0_rd_out[73]
    DIRECTION OUTPUT ;
    USE SIGNAL ;
    SHAPE ABUTMENT ;
    PORT
      LAYER M3 ;
      RECT 32.643 90.234 32.661 90.288 ;
    END
  END rw0_rd_out[73]
  PIN rw0_rd_out[74]
    DIRECTION OUTPUT ;
    USE SIGNAL ;
    SHAPE ABUTMENT ;
    PORT
      LAYER M3 ;
      RECT 34.551 90.234 34.569 90.288 ;
    END
  END rw0_rd_out[74]
  PIN rw0_rd_out[75]
    DIRECTION OUTPUT ;
    USE SIGNAL ;
    SHAPE ABUTMENT ;
    PORT
      LAYER M3 ;
      RECT 36.459 90.234 36.477 90.288 ;
    END
  END rw0_rd_out[75]
  PIN rw0_rd_out[76]
    DIRECTION OUTPUT ;
    USE SIGNAL ;
    SHAPE ABUTMENT ;
    PORT
      LAYER M3 ;
      RECT 38.367 90.234 38.385 90.288 ;
    END
  END rw0_rd_out[76]
  PIN rw0_rd_out[77]
    DIRECTION OUTPUT ;
    USE SIGNAL ;
    SHAPE ABUTMENT ;
    PORT
      LAYER M3 ;
      RECT 40.275 90.234 40.293 90.288 ;
    END
  END rw0_rd_out[77]
  PIN rw0_rd_out[78]
    DIRECTION OUTPUT ;
    USE SIGNAL ;
    SHAPE ABUTMENT ;
    PORT
      LAYER M3 ;
      RECT 42.183 90.234 42.201 90.288 ;
    END
  END rw0_rd_out[78]
  PIN rw0_rd_out[79]
    DIRECTION OUTPUT ;
    USE SIGNAL ;
    SHAPE ABUTMENT ;
    PORT
      LAYER M3 ;
      RECT 44.091 90.234 44.109 90.288 ;
    END
  END rw0_rd_out[79]
  PIN rw0_rd_out[80]
    DIRECTION OUTPUT ;
    USE SIGNAL ;
    SHAPE ABUTMENT ;
    PORT
      LAYER M3 ;
      RECT 45.999 90.234 46.017 90.288 ;
    END
  END rw0_rd_out[80]
  PIN rw0_rd_out[81]
    DIRECTION OUTPUT ;
    USE SIGNAL ;
    SHAPE ABUTMENT ;
    PORT
      LAYER M3 ;
      RECT 47.907 90.234 47.925 90.288 ;
    END
  END rw0_rd_out[81]
  PIN rw0_rd_out[82]
    DIRECTION OUTPUT ;
    USE SIGNAL ;
    SHAPE ABUTMENT ;
    PORT
      LAYER M3 ;
      RECT 49.815 90.234 49.833 90.288 ;
    END
  END rw0_rd_out[82]
  PIN rw0_rd_out[83]
    DIRECTION OUTPUT ;
    USE SIGNAL ;
    SHAPE ABUTMENT ;
    PORT
      LAYER M3 ;
      RECT 51.723 90.234 51.741 90.288 ;
    END
  END rw0_rd_out[83]
  PIN rw0_rd_out[84]
    DIRECTION OUTPUT ;
    USE SIGNAL ;
    SHAPE ABUTMENT ;
    PORT
      LAYER M3 ;
      RECT 53.631 90.234 53.649 90.288 ;
    END
  END rw0_rd_out[84]
  PIN rw0_rd_out[85]
    DIRECTION OUTPUT ;
    USE SIGNAL ;
    SHAPE ABUTMENT ;
    PORT
      LAYER M3 ;
      RECT 55.539 90.234 55.557 90.288 ;
    END
  END rw0_rd_out[85]
  PIN rw0_rd_out[86]
    DIRECTION OUTPUT ;
    USE SIGNAL ;
    SHAPE ABUTMENT ;
    PORT
      LAYER M3 ;
      RECT 57.447 90.234 57.465 90.288 ;
    END
  END rw0_rd_out[86]
  PIN rw0_rd_out[87]
    DIRECTION OUTPUT ;
    USE SIGNAL ;
    SHAPE ABUTMENT ;
    PORT
      LAYER M3 ;
      RECT 59.355 90.234 59.373 90.288 ;
    END
  END rw0_rd_out[87]
  PIN rw0_rd_out[88]
    DIRECTION OUTPUT ;
    USE SIGNAL ;
    SHAPE ABUTMENT ;
    PORT
      LAYER M3 ;
      RECT 61.263 90.234 61.281 90.288 ;
    END
  END rw0_rd_out[88]
  PIN rw0_rd_out[89]
    DIRECTION OUTPUT ;
    USE SIGNAL ;
    SHAPE ABUTMENT ;
    PORT
      LAYER M3 ;
      RECT 63.171 90.234 63.189 90.288 ;
    END
  END rw0_rd_out[89]
  PIN rw0_rd_out[90]
    DIRECTION OUTPUT ;
    USE SIGNAL ;
    SHAPE ABUTMENT ;
    PORT
      LAYER M3 ;
      RECT 65.079 90.234 65.097 90.288 ;
    END
  END rw0_rd_out[90]
  PIN rw0_rd_out[91]
    DIRECTION OUTPUT ;
    USE SIGNAL ;
    SHAPE ABUTMENT ;
    PORT
      LAYER M3 ;
      RECT 66.987 90.234 67.005 90.288 ;
    END
  END rw0_rd_out[91]
  PIN rw0_rd_out[92]
    DIRECTION OUTPUT ;
    USE SIGNAL ;
    SHAPE ABUTMENT ;
    PORT
      LAYER M3 ;
      RECT 68.895 90.234 68.913 90.288 ;
    END
  END rw0_rd_out[92]
  PIN rw0_rd_out[93]
    DIRECTION OUTPUT ;
    USE SIGNAL ;
    SHAPE ABUTMENT ;
    PORT
      LAYER M3 ;
      RECT 70.803 90.234 70.821 90.288 ;
    END
  END rw0_rd_out[93]
  PIN rw0_rd_out[94]
    DIRECTION OUTPUT ;
    USE SIGNAL ;
    SHAPE ABUTMENT ;
    PORT
      LAYER M3 ;
      RECT 72.711 90.234 72.729 90.288 ;
    END
  END rw0_rd_out[94]
  PIN rw0_rd_out[95]
    DIRECTION OUTPUT ;
    USE SIGNAL ;
    SHAPE ABUTMENT ;
    PORT
      LAYER M3 ;
      RECT 74.619 90.234 74.637 90.288 ;
    END
  END rw0_rd_out[95]
  PIN rw0_rd_out[96]
    DIRECTION OUTPUT ;
    USE SIGNAL ;
    SHAPE ABUTMENT ;
    PORT
      LAYER M3 ;
      RECT 76.527 90.234 76.545 90.288 ;
    END
  END rw0_rd_out[96]
  PIN rw0_rd_out[97]
    DIRECTION OUTPUT ;
    USE SIGNAL ;
    SHAPE ABUTMENT ;
    PORT
      LAYER M3 ;
      RECT 78.435 90.234 78.453 90.288 ;
    END
  END rw0_rd_out[97]
  PIN rw0_rd_out[98]
    DIRECTION OUTPUT ;
    USE SIGNAL ;
    SHAPE ABUTMENT ;
    PORT
      LAYER M3 ;
      RECT 80.343 90.234 80.361 90.288 ;
    END
  END rw0_rd_out[98]
  PIN rw0_rd_out[99]
    DIRECTION OUTPUT ;
    USE SIGNAL ;
    SHAPE ABUTMENT ;
    PORT
      LAYER M3 ;
      RECT 82.251 90.234 82.269 90.288 ;
    END
  END rw0_rd_out[99]
  PIN rw0_rd_out[100]
    DIRECTION OUTPUT ;
    USE SIGNAL ;
    SHAPE ABUTMENT ;
    PORT
      LAYER M3 ;
      RECT 84.159 90.234 84.177 90.288 ;
    END
  END rw0_rd_out[100]
  PIN rw0_rd_out[101]
    DIRECTION OUTPUT ;
    USE SIGNAL ;
    SHAPE ABUTMENT ;
    PORT
      LAYER M3 ;
      RECT 86.067 90.234 86.085 90.288 ;
    END
  END rw0_rd_out[101]
  PIN rw0_rd_out[102]
    DIRECTION OUTPUT ;
    USE SIGNAL ;
    SHAPE ABUTMENT ;
    PORT
      LAYER M3 ;
      RECT 87.975 90.234 87.993 90.288 ;
    END
  END rw0_rd_out[102]
  PIN rw0_rd_out[103]
    DIRECTION OUTPUT ;
    USE SIGNAL ;
    SHAPE ABUTMENT ;
    PORT
      LAYER M3 ;
      RECT 89.883 90.234 89.901 90.288 ;
    END
  END rw0_rd_out[103]
  PIN rw0_rd_out[104]
    DIRECTION OUTPUT ;
    USE SIGNAL ;
    SHAPE ABUTMENT ;
    PORT
      LAYER M3 ;
      RECT 91.791 90.234 91.809 90.288 ;
    END
  END rw0_rd_out[104]
  PIN rw0_rd_out[105]
    DIRECTION OUTPUT ;
    USE SIGNAL ;
    SHAPE ABUTMENT ;
    PORT
      LAYER M3 ;
      RECT 93.699 90.234 93.717 90.288 ;
    END
  END rw0_rd_out[105]
  PIN rw0_rd_out[106]
    DIRECTION OUTPUT ;
    USE SIGNAL ;
    SHAPE ABUTMENT ;
    PORT
      LAYER M3 ;
      RECT 95.607 90.234 95.625 90.288 ;
    END
  END rw0_rd_out[106]
  PIN rw0_rd_out[107]
    DIRECTION OUTPUT ;
    USE SIGNAL ;
    SHAPE ABUTMENT ;
    PORT
      LAYER M3 ;
      RECT 97.515 90.234 97.533 90.288 ;
    END
  END rw0_rd_out[107]
  PIN rw0_rd_out[108]
    DIRECTION OUTPUT ;
    USE SIGNAL ;
    SHAPE ABUTMENT ;
    PORT
      LAYER M3 ;
      RECT 99.423 90.234 99.441 90.288 ;
    END
  END rw0_rd_out[108]
  PIN rw0_rd_out[109]
    DIRECTION OUTPUT ;
    USE SIGNAL ;
    SHAPE ABUTMENT ;
    PORT
      LAYER M3 ;
      RECT 101.331 90.234 101.349 90.288 ;
    END
  END rw0_rd_out[109]
  PIN rw0_rd_out[110]
    DIRECTION OUTPUT ;
    USE SIGNAL ;
    SHAPE ABUTMENT ;
    PORT
      LAYER M3 ;
      RECT 103.239 90.234 103.257 90.288 ;
    END
  END rw0_rd_out[110]
  PIN rw0_rd_out[111]
    DIRECTION OUTPUT ;
    USE SIGNAL ;
    SHAPE ABUTMENT ;
    PORT
      LAYER M3 ;
      RECT 105.147 90.234 105.165 90.288 ;
    END
  END rw0_rd_out[111]
  PIN rw0_rd_out[112]
    DIRECTION OUTPUT ;
    USE SIGNAL ;
    SHAPE ABUTMENT ;
    PORT
      LAYER M3 ;
      RECT 107.055 90.234 107.073 90.288 ;
    END
  END rw0_rd_out[112]
  PIN rw0_rd_out[113]
    DIRECTION OUTPUT ;
    USE SIGNAL ;
    SHAPE ABUTMENT ;
    PORT
      LAYER M3 ;
      RECT 108.963 90.234 108.981 90.288 ;
    END
  END rw0_rd_out[113]
  PIN rw0_rd_out[114]
    DIRECTION OUTPUT ;
    USE SIGNAL ;
    SHAPE ABUTMENT ;
    PORT
      LAYER M3 ;
      RECT 110.871 90.234 110.889 90.288 ;
    END
  END rw0_rd_out[114]
  PIN rw0_rd_out[115]
    DIRECTION OUTPUT ;
    USE SIGNAL ;
    SHAPE ABUTMENT ;
    PORT
      LAYER M3 ;
      RECT 112.779 90.234 112.797 90.288 ;
    END
  END rw0_rd_out[115]
  PIN rw0_rd_out[116]
    DIRECTION OUTPUT ;
    USE SIGNAL ;
    SHAPE ABUTMENT ;
    PORT
      LAYER M3 ;
      RECT 114.687 90.234 114.705 90.288 ;
    END
  END rw0_rd_out[116]
  PIN rw0_rd_out[117]
    DIRECTION OUTPUT ;
    USE SIGNAL ;
    SHAPE ABUTMENT ;
    PORT
      LAYER M3 ;
      RECT 116.595 90.234 116.613 90.288 ;
    END
  END rw0_rd_out[117]
  PIN rw0_rd_out[118]
    DIRECTION OUTPUT ;
    USE SIGNAL ;
    SHAPE ABUTMENT ;
    PORT
      LAYER M3 ;
      RECT 118.503 90.234 118.521 90.288 ;
    END
  END rw0_rd_out[118]
  PIN rw0_rd_out[119]
    DIRECTION OUTPUT ;
    USE SIGNAL ;
    SHAPE ABUTMENT ;
    PORT
      LAYER M3 ;
      RECT 120.411 90.234 120.429 90.288 ;
    END
  END rw0_rd_out[119]
  PIN rw0_rd_out[120]
    DIRECTION OUTPUT ;
    USE SIGNAL ;
    SHAPE ABUTMENT ;
    PORT
      LAYER M3 ;
      RECT 122.319 90.234 122.337 90.288 ;
    END
  END rw0_rd_out[120]
  PIN rw0_rd_out[121]
    DIRECTION OUTPUT ;
    USE SIGNAL ;
    SHAPE ABUTMENT ;
    PORT
      LAYER M3 ;
      RECT 124.227 90.234 124.245 90.288 ;
    END
  END rw0_rd_out[121]
  PIN rw0_rd_out[122]
    DIRECTION OUTPUT ;
    USE SIGNAL ;
    SHAPE ABUTMENT ;
    PORT
      LAYER M3 ;
      RECT 126.135 90.234 126.153 90.288 ;
    END
  END rw0_rd_out[122]
  PIN rw0_rd_out[123]
    DIRECTION OUTPUT ;
    USE SIGNAL ;
    SHAPE ABUTMENT ;
    PORT
      LAYER M3 ;
      RECT 128.043 90.234 128.061 90.288 ;
    END
  END rw0_rd_out[123]
  PIN rw0_rd_out[124]
    DIRECTION OUTPUT ;
    USE SIGNAL ;
    SHAPE ABUTMENT ;
    PORT
      LAYER M3 ;
      RECT 129.951 90.234 129.969 90.288 ;
    END
  END rw0_rd_out[124]
  PIN rw0_rd_out[125]
    DIRECTION OUTPUT ;
    USE SIGNAL ;
    SHAPE ABUTMENT ;
    PORT
      LAYER M3 ;
      RECT 131.859 90.234 131.877 90.288 ;
    END
  END rw0_rd_out[125]
  PIN rw0_rd_out[126]
    DIRECTION OUTPUT ;
    USE SIGNAL ;
    SHAPE ABUTMENT ;
    PORT
      LAYER M3 ;
      RECT 133.767 90.234 133.785 90.288 ;
    END
  END rw0_rd_out[126]
  PIN rw0_rd_out[127]
    DIRECTION OUTPUT ;
    USE SIGNAL ;
    SHAPE ABUTMENT ;
    PORT
      LAYER M3 ;
      RECT 135.675 90.234 135.693 90.288 ;
    END
  END rw0_rd_out[127]
  PIN rw0_addr_in[0]
    DIRECTION INPUT ;
    USE SIGNAL ;
    SHAPE ABUTMENT ;
    PORT
      LAYER M4 ;
      RECT 0.000 78.036 0.072 78.060 ;
    END
  END rw0_addr_in[0]
  PIN rw0_addr_in[1]
    DIRECTION INPUT ;
    USE SIGNAL ;
    SHAPE ABUTMENT ;
    PORT
      LAYER M4 ;
      RECT 0.000 80.196 0.072 80.220 ;
    END
  END rw0_addr_in[1]
  PIN rw0_addr_in[2]
    DIRECTION INPUT ;
    USE SIGNAL ;
    SHAPE ABUTMENT ;
    PORT
      LAYER M4 ;
      RECT 0.000 82.356 0.072 82.380 ;
    END
  END rw0_addr_in[2]
  PIN rw0_addr_in[3]
    DIRECTION INPUT ;
    USE SIGNAL ;
    SHAPE ABUTMENT ;
    PORT
      LAYER M4 ;
      RECT 0.000 84.516 0.072 84.540 ;
    END
  END rw0_addr_in[3]
  PIN rw0_addr_in[4]
    DIRECTION INPUT ;
    USE SIGNAL ;
    SHAPE ABUTMENT ;
    PORT
      LAYER M4 ;
      RECT 0.000 86.676 0.072 86.700 ;
    END
  END rw0_addr_in[4]
  PIN rw0_addr_in[5]
    DIRECTION INPUT ;
    USE SIGNAL ;
    SHAPE ABUTMENT ;
    PORT
      LAYER M4 ;
      RECT 144.389 78.036 144.461 78.060 ;
    END
  END rw0_addr_in[5]
  PIN rw0_addr_in[6]
    DIRECTION INPUT ;
    USE SIGNAL ;
    SHAPE ABUTMENT ;
    PORT
      LAYER M4 ;
      RECT 144.389 80.196 144.461 80.220 ;
    END
  END rw0_addr_in[6]
  PIN rw0_addr_in[7]
    DIRECTION INPUT ;
    USE SIGNAL ;
    SHAPE ABUTMENT ;
    PORT
      LAYER M4 ;
      RECT 144.389 82.356 144.461 82.380 ;
    END
  END rw0_addr_in[7]
  PIN rw0_addr_in[8]
    DIRECTION INPUT ;
    USE SIGNAL ;
    SHAPE ABUTMENT ;
    PORT
      LAYER M4 ;
      RECT 144.389 84.516 144.461 84.540 ;
    END
  END rw0_addr_in[8]
  PIN rw0_we_in
    DIRECTION INPUT ;
    USE SIGNAL ;
    SHAPE ABUTMENT ;
    PORT
      LAYER M3 ;
      RECT 137.583 90.234 137.601 90.288 ;
    END
  END rw0_we_in
  PIN rw0_ce_in
    DIRECTION INPUT ;
    USE SIGNAL ;
    SHAPE ABUTMENT ;
    PORT
      LAYER M3 ;
      RECT 139.491 90.234 139.509 90.288 ;
    END
  END rw0_ce_in
  PIN rw0_clk
    DIRECTION INPUT ;
    USE SIGNAL ;
    SHAPE ABUTMENT ;
    PORT
      LAYER M3 ;
      RECT 141.399 90.234 141.417 90.288 ;
    END
  END rw0_clk
  PIN VSS
    DIRECTION INOUT ;
    USE GROUND ;
    PORT
      LAYER M4 ;
      RECT 0.216 0.240 144.245 0.336 ;
      RECT 0.216 1.008 144.245 1.104 ;
      RECT 0.216 1.776 144.245 1.872 ;
      RECT 0.216 2.544 144.245 2.640 ;
      RECT 0.216 3.312 144.245 3.408 ;
      RECT 0.216 4.080 144.245 4.176 ;
      RECT 0.216 4.848 144.245 4.944 ;
      RECT 0.216 5.616 144.245 5.712 ;
      RECT 0.216 6.384 144.245 6.480 ;
      RECT 0.216 7.152 144.245 7.248 ;
      RECT 0.216 7.920 144.245 8.016 ;
      RECT 0.216 8.688 144.245 8.784 ;
      RECT 0.216 9.456 144.245 9.552 ;
      RECT 0.216 10.224 144.245 10.320 ;
      RECT 0.216 10.992 144.245 11.088 ;
      RECT 0.216 11.760 144.245 11.856 ;
      RECT 0.216 12.528 144.245 12.624 ;
      RECT 0.216 13.296 144.245 13.392 ;
      RECT 0.216 14.064 144.245 14.160 ;
      RECT 0.216 14.832 144.245 14.928 ;
      RECT 0.216 15.600 144.245 15.696 ;
      RECT 0.216 16.368 144.245 16.464 ;
      RECT 0.216 17.136 144.245 17.232 ;
      RECT 0.216 17.904 144.245 18.000 ;
      RECT 0.216 18.672 144.245 18.768 ;
      RECT 0.216 19.440 144.245 19.536 ;
      RECT 0.216 20.208 144.245 20.304 ;
      RECT 0.216 20.976 144.245 21.072 ;
      RECT 0.216 21.744 144.245 21.840 ;
      RECT 0.216 22.512 144.245 22.608 ;
      RECT 0.216 23.280 144.245 23.376 ;
      RECT 0.216 24.048 144.245 24.144 ;
      RECT 0.216 24.816 144.245 24.912 ;
      RECT 0.216 25.584 144.245 25.680 ;
      RECT 0.216 26.352 144.245 26.448 ;
      RECT 0.216 27.120 144.245 27.216 ;
      RECT 0.216 27.888 144.245 27.984 ;
      RECT 0.216 28.656 144.245 28.752 ;
      RECT 0.216 29.424 144.245 29.520 ;
      RECT 0.216 30.192 144.245 30.288 ;
      RECT 0.216 30.960 144.245 31.056 ;
      RECT 0.216 31.728 144.245 31.824 ;
      RECT 0.216 32.496 144.245 32.592 ;
      RECT 0.216 33.264 144.245 33.360 ;
      RECT 0.216 34.032 144.245 34.128 ;
      RECT 0.216 34.800 144.245 34.896 ;
      RECT 0.216 35.568 144.245 35.664 ;
      RECT 0.216 36.336 144.245 36.432 ;
      RECT 0.216 37.104 144.245 37.200 ;
      RECT 0.216 37.872 144.245 37.968 ;
      RECT 0.216 38.640 144.245 38.736 ;
      RECT 0.216 39.408 144.245 39.504 ;
      RECT 0.216 40.176 144.245 40.272 ;
      RECT 0.216 40.944 144.245 41.040 ;
      RECT 0.216 41.712 144.245 41.808 ;
      RECT 0.216 42.480 144.245 42.576 ;
      RECT 0.216 43.248 144.245 43.344 ;
      RECT 0.216 44.016 144.245 44.112 ;
      RECT 0.216 44.784 144.245 44.880 ;
      RECT 0.216 45.552 144.245 45.648 ;
      RECT 0.216 46.320 144.245 46.416 ;
      RECT 0.216 47.088 144.245 47.184 ;
      RECT 0.216 47.856 144.245 47.952 ;
      RECT 0.216 48.624 144.245 48.720 ;
      RECT 0.216 49.392 144.245 49.488 ;
      RECT 0.216 50.160 144.245 50.256 ;
      RECT 0.216 50.928 144.245 51.024 ;
      RECT 0.216 51.696 144.245 51.792 ;
      RECT 0.216 52.464 144.245 52.560 ;
      RECT 0.216 53.232 144.245 53.328 ;
      RECT 0.216 54.000 144.245 54.096 ;
      RECT 0.216 54.768 144.245 54.864 ;
      RECT 0.216 55.536 144.245 55.632 ;
      RECT 0.216 56.304 144.245 56.400 ;
      RECT 0.216 57.072 144.245 57.168 ;
      RECT 0.216 57.840 144.245 57.936 ;
      RECT 0.216 58.608 144.245 58.704 ;
      RECT 0.216 59.376 144.245 59.472 ;
      RECT 0.216 60.144 144.245 60.240 ;
      RECT 0.216 60.912 144.245 61.008 ;
      RECT 0.216 61.680 144.245 61.776 ;
      RECT 0.216 62.448 144.245 62.544 ;
      RECT 0.216 63.216 144.245 63.312 ;
      RECT 0.216 63.984 144.245 64.080 ;
      RECT 0.216 64.752 144.245 64.848 ;
      RECT 0.216 65.520 144.245 65.616 ;
      RECT 0.216 66.288 144.245 66.384 ;
      RECT 0.216 67.056 144.245 67.152 ;
      RECT 0.216 67.824 144.245 67.920 ;
      RECT 0.216 68.592 144.245 68.688 ;
      RECT 0.216 69.360 144.245 69.456 ;
      RECT 0.216 70.128 144.245 70.224 ;
      RECT 0.216 70.896 144.245 70.992 ;
      RECT 0.216 71.664 144.245 71.760 ;
      RECT 0.216 72.432 144.245 72.528 ;
      RECT 0.216 73.200 144.245 73.296 ;
      RECT 0.216 73.968 144.245 74.064 ;
      RECT 0.216 74.736 144.245 74.832 ;
      RECT 0.216 75.504 144.245 75.600 ;
      RECT 0.216 76.272 144.245 76.368 ;
      RECT 0.216 77.040 144.245 77.136 ;
      RECT 0.216 77.808 144.245 77.904 ;
      RECT 0.216 78.576 144.245 78.672 ;
      RECT 0.216 79.344 144.245 79.440 ;
      RECT 0.216 80.112 144.245 80.208 ;
      RECT 0.216 80.880 144.245 80.976 ;
      RECT 0.216 81.648 144.245 81.744 ;
      RECT 0.216 82.416 144.245 82.512 ;
      RECT 0.216 83.184 144.245 83.280 ;
      RECT 0.216 83.952 144.245 84.048 ;
      RECT 0.216 84.720 144.245 84.816 ;
      RECT 0.216 85.488 144.245 85.584 ;
      RECT 0.216 86.256 144.245 86.352 ;
      RECT 0.216 87.024 144.245 87.120 ;
      RECT 0.216 87.792 144.245 87.888 ;
      RECT 0.216 88.560 144.245 88.656 ;
      RECT 0.216 89.328 144.245 89.424 ;
      RECT 0.216 90.096 144.245 90.192 ;
    END
  END VSS
  PIN VDD
    DIRECTION INOUT ;
    USE POWER ;
    PORT
      LAYER M4 ;
      RECT 0.216 0.240 144.245 0.336 ;
      RECT 0.216 1.008 144.245 1.104 ;
      RECT 0.216 1.776 144.245 1.872 ;
      RECT 0.216 2.544 144.245 2.640 ;
      RECT 0.216 3.312 144.245 3.408 ;
      RECT 0.216 4.080 144.245 4.176 ;
      RECT 0.216 4.848 144.245 4.944 ;
      RECT 0.216 5.616 144.245 5.712 ;
      RECT 0.216 6.384 144.245 6.480 ;
      RECT 0.216 7.152 144.245 7.248 ;
      RECT 0.216 7.920 144.245 8.016 ;
      RECT 0.216 8.688 144.245 8.784 ;
      RECT 0.216 9.456 144.245 9.552 ;
      RECT 0.216 10.224 144.245 10.320 ;
      RECT 0.216 10.992 144.245 11.088 ;
      RECT 0.216 11.760 144.245 11.856 ;
      RECT 0.216 12.528 144.245 12.624 ;
      RECT 0.216 13.296 144.245 13.392 ;
      RECT 0.216 14.064 144.245 14.160 ;
      RECT 0.216 14.832 144.245 14.928 ;
      RECT 0.216 15.600 144.245 15.696 ;
      RECT 0.216 16.368 144.245 16.464 ;
      RECT 0.216 17.136 144.245 17.232 ;
      RECT 0.216 17.904 144.245 18.000 ;
      RECT 0.216 18.672 144.245 18.768 ;
      RECT 0.216 19.440 144.245 19.536 ;
      RECT 0.216 20.208 144.245 20.304 ;
      RECT 0.216 20.976 144.245 21.072 ;
      RECT 0.216 21.744 144.245 21.840 ;
      RECT 0.216 22.512 144.245 22.608 ;
      RECT 0.216 23.280 144.245 23.376 ;
      RECT 0.216 24.048 144.245 24.144 ;
      RECT 0.216 24.816 144.245 24.912 ;
      RECT 0.216 25.584 144.245 25.680 ;
      RECT 0.216 26.352 144.245 26.448 ;
      RECT 0.216 27.120 144.245 27.216 ;
      RECT 0.216 27.888 144.245 27.984 ;
      RECT 0.216 28.656 144.245 28.752 ;
      RECT 0.216 29.424 144.245 29.520 ;
      RECT 0.216 30.192 144.245 30.288 ;
      RECT 0.216 30.960 144.245 31.056 ;
      RECT 0.216 31.728 144.245 31.824 ;
      RECT 0.216 32.496 144.245 32.592 ;
      RECT 0.216 33.264 144.245 33.360 ;
      RECT 0.216 34.032 144.245 34.128 ;
      RECT 0.216 34.800 144.245 34.896 ;
      RECT 0.216 35.568 144.245 35.664 ;
      RECT 0.216 36.336 144.245 36.432 ;
      RECT 0.216 37.104 144.245 37.200 ;
      RECT 0.216 37.872 144.245 37.968 ;
      RECT 0.216 38.640 144.245 38.736 ;
      RECT 0.216 39.408 144.245 39.504 ;
      RECT 0.216 40.176 144.245 40.272 ;
      RECT 0.216 40.944 144.245 41.040 ;
      RECT 0.216 41.712 144.245 41.808 ;
      RECT 0.216 42.480 144.245 42.576 ;
      RECT 0.216 43.248 144.245 43.344 ;
      RECT 0.216 44.016 144.245 44.112 ;
      RECT 0.216 44.784 144.245 44.880 ;
      RECT 0.216 45.552 144.245 45.648 ;
      RECT 0.216 46.320 144.245 46.416 ;
      RECT 0.216 47.088 144.245 47.184 ;
      RECT 0.216 47.856 144.245 47.952 ;
      RECT 0.216 48.624 144.245 48.720 ;
      RECT 0.216 49.392 144.245 49.488 ;
      RECT 0.216 50.160 144.245 50.256 ;
      RECT 0.216 50.928 144.245 51.024 ;
      RECT 0.216 51.696 144.245 51.792 ;
      RECT 0.216 52.464 144.245 52.560 ;
      RECT 0.216 53.232 144.245 53.328 ;
      RECT 0.216 54.000 144.245 54.096 ;
      RECT 0.216 54.768 144.245 54.864 ;
      RECT 0.216 55.536 144.245 55.632 ;
      RECT 0.216 56.304 144.245 56.400 ;
      RECT 0.216 57.072 144.245 57.168 ;
      RECT 0.216 57.840 144.245 57.936 ;
      RECT 0.216 58.608 144.245 58.704 ;
      RECT 0.216 59.376 144.245 59.472 ;
      RECT 0.216 60.144 144.245 60.240 ;
      RECT 0.216 60.912 144.245 61.008 ;
      RECT 0.216 61.680 144.245 61.776 ;
      RECT 0.216 62.448 144.245 62.544 ;
      RECT 0.216 63.216 144.245 63.312 ;
      RECT 0.216 63.984 144.245 64.080 ;
      RECT 0.216 64.752 144.245 64.848 ;
      RECT 0.216 65.520 144.245 65.616 ;
      RECT 0.216 66.288 144.245 66.384 ;
      RECT 0.216 67.056 144.245 67.152 ;
      RECT 0.216 67.824 144.245 67.920 ;
      RECT 0.216 68.592 144.245 68.688 ;
      RECT 0.216 69.360 144.245 69.456 ;
      RECT 0.216 70.128 144.245 70.224 ;
      RECT 0.216 70.896 144.245 70.992 ;
      RECT 0.216 71.664 144.245 71.760 ;
      RECT 0.216 72.432 144.245 72.528 ;
      RECT 0.216 73.200 144.245 73.296 ;
      RECT 0.216 73.968 144.245 74.064 ;
      RECT 0.216 74.736 144.245 74.832 ;
      RECT 0.216 75.504 144.245 75.600 ;
      RECT 0.216 76.272 144.245 76.368 ;
      RECT 0.216 77.040 144.245 77.136 ;
      RECT 0.216 77.808 144.245 77.904 ;
      RECT 0.216 78.576 144.245 78.672 ;
      RECT 0.216 79.344 144.245 79.440 ;
      RECT 0.216 80.112 144.245 80.208 ;
      RECT 0.216 80.880 144.245 80.976 ;
      RECT 0.216 81.648 144.245 81.744 ;
      RECT 0.216 82.416 144.245 82.512 ;
      RECT 0.216 83.184 144.245 83.280 ;
      RECT 0.216 83.952 144.245 84.048 ;
      RECT 0.216 84.720 144.245 84.816 ;
      RECT 0.216 85.488 144.245 85.584 ;
      RECT 0.216 86.256 144.245 86.352 ;
      RECT 0.216 87.024 144.245 87.120 ;
      RECT 0.216 87.792 144.245 87.888 ;
      RECT 0.216 88.560 144.245 88.656 ;
      RECT 0.216 89.328 144.245 89.424 ;
      RECT 0.216 90.096 144.245 90.192 ;
    END
  END VDD
  OBS
    LAYER M1 ;
    RECT 0 0 144.461 90.288 ;
    LAYER M2 ;
    RECT 0 0 144.461 90.288 ;
    LAYER M3 ;
    RECT 0 0 144.461 90.288 ;
    LAYER M4 ;
    RECT 0 0 144.461 90.288 ;
  END
END fakeram_512x128_1rw

END LIBRARY
